VERSION 5.7 ;
  NOWIREEXTENSIONATPIN ON ;
  DIVIDERCHAR "/" ;
  BUSBITCHARS "[]" ;
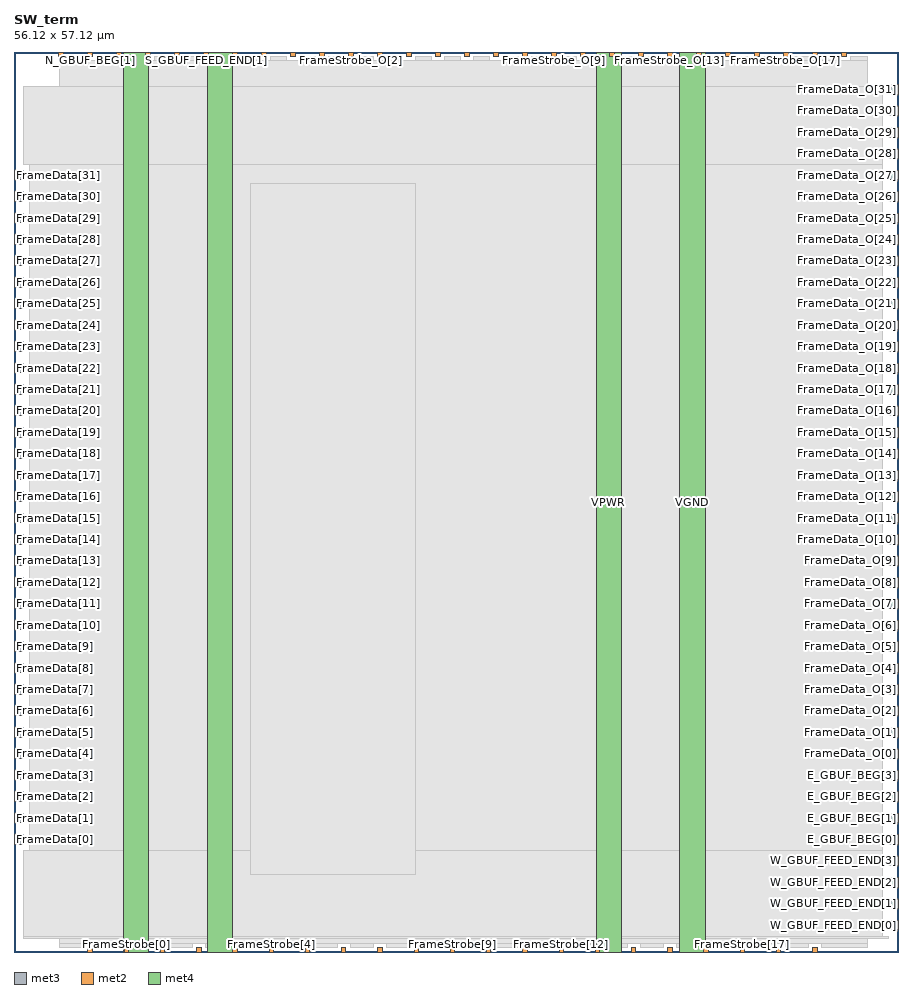
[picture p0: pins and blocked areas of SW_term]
MACRO SW_term
  CLASS BLOCK ;
  FOREIGN SW_term ;
  ORIGIN 0.000 0.000 ;
  SIZE 56.120 BY 57.120 ;
  PIN E_GBUF_BEG[0]
    DIRECTION OUTPUT ;
    USE SIGNAL ;
    ANTENNADIFFAREA 0.702900 ;
    PORT
      LAYER met3 ;
        RECT 55.520 6.840 56.120 7.440 ;
    END
  END E_GBUF_BEG[0]
  PIN E_GBUF_BEG[1]
    DIRECTION OUTPUT ;
    USE SIGNAL ;
    ANTENNADIFFAREA 0.702900 ;
    PORT
      LAYER met3 ;
        RECT 55.520 8.200 56.120 8.800 ;
    END
  END E_GBUF_BEG[1]
  PIN E_GBUF_BEG[2]
    DIRECTION OUTPUT ;
    USE SIGNAL ;
    ANTENNADIFFAREA 0.702900 ;
    PORT
      LAYER met3 ;
        RECT 55.520 9.560 56.120 10.160 ;
    END
  END E_GBUF_BEG[2]
  PIN E_GBUF_BEG[3]
    DIRECTION OUTPUT ;
    USE SIGNAL ;
    ANTENNADIFFAREA 0.702900 ;
    PORT
      LAYER met3 ;
        RECT 55.520 10.920 56.120 11.520 ;
    END
  END E_GBUF_BEG[3]
  PIN FrameData[0]
    DIRECTION INPUT ;
    USE SIGNAL ;
    ANTENNAGATEAREA 0.159000 ;
    PORT
      LAYER met3 ;
        RECT 0.000 6.840 0.600 7.440 ;
    END
  END FrameData[0]
  PIN FrameData[10]
    DIRECTION INPUT ;
    USE SIGNAL ;
    ANTENNAGATEAREA 0.159000 ;
    PORT
      LAYER met3 ;
        RECT 0.000 20.440 0.600 21.040 ;
    END
  END FrameData[10]
  PIN FrameData[11]
    DIRECTION INPUT ;
    USE SIGNAL ;
    ANTENNAGATEAREA 0.159000 ;
    PORT
      LAYER met3 ;
        RECT 0.000 21.800 0.600 22.400 ;
    END
  END FrameData[11]
  PIN FrameData[12]
    DIRECTION INPUT ;
    USE SIGNAL ;
    ANTENNAGATEAREA 0.318000 ;
    PORT
      LAYER met3 ;
        RECT 0.000 23.160 0.600 23.760 ;
    END
  END FrameData[12]
  PIN FrameData[13]
    DIRECTION INPUT ;
    USE SIGNAL ;
    ANTENNAGATEAREA 0.318000 ;
    PORT
      LAYER met3 ;
        RECT 0.000 24.520 0.600 25.120 ;
    END
  END FrameData[13]
  PIN FrameData[14]
    DIRECTION INPUT ;
    USE SIGNAL ;
    ANTENNAGATEAREA 0.318000 ;
    PORT
      LAYER met3 ;
        RECT 0.000 25.880 0.600 26.480 ;
    END
  END FrameData[14]
  PIN FrameData[15]
    DIRECTION INPUT ;
    USE SIGNAL ;
    ANTENNAGATEAREA 0.318000 ;
    PORT
      LAYER met3 ;
        RECT 0.000 27.240 0.600 27.840 ;
    END
  END FrameData[15]
  PIN FrameData[16]
    DIRECTION INPUT ;
    USE SIGNAL ;
    ANTENNAGATEAREA 0.318000 ;
    PORT
      LAYER met3 ;
        RECT 0.000 28.600 0.600 29.200 ;
    END
  END FrameData[16]
  PIN FrameData[17]
    DIRECTION INPUT ;
    USE SIGNAL ;
    ANTENNAGATEAREA 0.318000 ;
    PORT
      LAYER met3 ;
        RECT 0.000 29.960 0.600 30.560 ;
    END
  END FrameData[17]
  PIN FrameData[18]
    DIRECTION INPUT ;
    USE SIGNAL ;
    ANTENNAGATEAREA 0.318000 ;
    PORT
      LAYER met3 ;
        RECT 0.000 31.320 0.600 31.920 ;
    END
  END FrameData[18]
  PIN FrameData[19]
    DIRECTION INPUT ;
    USE SIGNAL ;
    ANTENNAGATEAREA 0.318000 ;
    PORT
      LAYER met3 ;
        RECT 0.000 32.680 0.600 33.280 ;
    END
  END FrameData[19]
  PIN FrameData[1]
    DIRECTION INPUT ;
    USE SIGNAL ;
    ANTENNAGATEAREA 0.159000 ;
    PORT
      LAYER met3 ;
        RECT 0.000 8.200 0.600 8.800 ;
    END
  END FrameData[1]
  PIN FrameData[20]
    DIRECTION INPUT ;
    USE SIGNAL ;
    ANTENNAGATEAREA 0.318000 ;
    PORT
      LAYER met3 ;
        RECT 0.000 34.040 0.600 34.640 ;
    END
  END FrameData[20]
  PIN FrameData[21]
    DIRECTION INPUT ;
    USE SIGNAL ;
    ANTENNAGATEAREA 0.318000 ;
    PORT
      LAYER met3 ;
        RECT 0.000 35.400 0.600 36.000 ;
    END
  END FrameData[21]
  PIN FrameData[22]
    DIRECTION INPUT ;
    USE SIGNAL ;
    ANTENNAGATEAREA 0.318000 ;
    PORT
      LAYER met3 ;
        RECT 0.000 36.760 0.600 37.360 ;
    END
  END FrameData[22]
  PIN FrameData[23]
    DIRECTION INPUT ;
    USE SIGNAL ;
    ANTENNAGATEAREA 0.318000 ;
    PORT
      LAYER met3 ;
        RECT 0.000 38.120 0.600 38.720 ;
    END
  END FrameData[23]
  PIN FrameData[24]
    DIRECTION INPUT ;
    USE SIGNAL ;
    ANTENNAGATEAREA 0.318000 ;
    PORT
      LAYER met3 ;
        RECT 0.000 39.480 0.600 40.080 ;
    END
  END FrameData[24]
  PIN FrameData[25]
    DIRECTION INPUT ;
    USE SIGNAL ;
    ANTENNAGATEAREA 0.318000 ;
    PORT
      LAYER met3 ;
        RECT 0.000 40.840 0.600 41.440 ;
    END
  END FrameData[25]
  PIN FrameData[26]
    DIRECTION INPUT ;
    USE SIGNAL ;
    ANTENNAGATEAREA 0.318000 ;
    PORT
      LAYER met3 ;
        RECT 0.000 42.200 0.600 42.800 ;
    END
  END FrameData[26]
  PIN FrameData[27]
    DIRECTION INPUT ;
    USE SIGNAL ;
    ANTENNAGATEAREA 0.318000 ;
    PORT
      LAYER met3 ;
        RECT 0.000 43.560 0.600 44.160 ;
    END
  END FrameData[27]
  PIN FrameData[28]
    DIRECTION INPUT ;
    USE SIGNAL ;
    ANTENNAGATEAREA 0.318000 ;
    PORT
      LAYER met3 ;
        RECT 0.000 44.920 0.600 45.520 ;
    END
  END FrameData[28]
  PIN FrameData[29]
    DIRECTION INPUT ;
    USE SIGNAL ;
    ANTENNAGATEAREA 0.318000 ;
    PORT
      LAYER met3 ;
        RECT 0.000 46.280 0.600 46.880 ;
    END
  END FrameData[29]
  PIN FrameData[2]
    DIRECTION INPUT ;
    USE SIGNAL ;
    ANTENNAGATEAREA 0.159000 ;
    PORT
      LAYER met3 ;
        RECT 0.000 9.560 0.600 10.160 ;
    END
  END FrameData[2]
  PIN FrameData[30]
    DIRECTION INPUT ;
    USE SIGNAL ;
    ANTENNAGATEAREA 0.318000 ;
    PORT
      LAYER met3 ;
        RECT 0.000 47.640 0.600 48.240 ;
    END
  END FrameData[30]
  PIN FrameData[31]
    DIRECTION INPUT ;
    USE SIGNAL ;
    ANTENNAGATEAREA 0.318000 ;
    PORT
      LAYER met3 ;
        RECT 0.000 49.000 0.600 49.600 ;
    END
  END FrameData[31]
  PIN FrameData[3]
    DIRECTION INPUT ;
    USE SIGNAL ;
    ANTENNAGATEAREA 0.159000 ;
    PORT
      LAYER met3 ;
        RECT 0.000 10.920 0.600 11.520 ;
    END
  END FrameData[3]
  PIN FrameData[4]
    DIRECTION INPUT ;
    USE SIGNAL ;
    ANTENNAGATEAREA 0.159000 ;
    PORT
      LAYER met3 ;
        RECT 0.000 12.280 0.600 12.880 ;
    END
  END FrameData[4]
  PIN FrameData[5]
    DIRECTION INPUT ;
    USE SIGNAL ;
    ANTENNAGATEAREA 0.159000 ;
    PORT
      LAYER met3 ;
        RECT 0.000 13.640 0.600 14.240 ;
    END
  END FrameData[5]
  PIN FrameData[6]
    DIRECTION INPUT ;
    USE SIGNAL ;
    ANTENNAGATEAREA 0.159000 ;
    PORT
      LAYER met3 ;
        RECT 0.000 15.000 0.600 15.600 ;
    END
  END FrameData[6]
  PIN FrameData[7]
    DIRECTION INPUT ;
    USE SIGNAL ;
    ANTENNAGATEAREA 0.159000 ;
    PORT
      LAYER met3 ;
        RECT 0.000 16.360 0.600 16.960 ;
    END
  END FrameData[7]
  PIN FrameData[8]
    DIRECTION INPUT ;
    USE SIGNAL ;
    ANTENNAGATEAREA 0.159000 ;
    PORT
      LAYER met3 ;
        RECT 0.000 17.720 0.600 18.320 ;
    END
  END FrameData[8]
  PIN FrameData[9]
    DIRECTION INPUT ;
    USE SIGNAL ;
    ANTENNAGATEAREA 0.159000 ;
    PORT
      LAYER met3 ;
        RECT 0.000 19.080 0.600 19.680 ;
    END
  END FrameData[9]
  PIN FrameData_O[0]
    DIRECTION OUTPUT ;
    USE SIGNAL ;
    ANTENNADIFFAREA 0.702900 ;
    PORT
      LAYER met3 ;
        RECT 55.520 12.280 56.120 12.880 ;
    END
  END FrameData_O[0]
  PIN FrameData_O[10]
    DIRECTION OUTPUT ;
    USE SIGNAL ;
    ANTENNADIFFAREA 0.702900 ;
    PORT
      LAYER met3 ;
        RECT 55.520 25.880 56.120 26.480 ;
    END
  END FrameData_O[10]
  PIN FrameData_O[11]
    DIRECTION OUTPUT ;
    USE SIGNAL ;
    ANTENNADIFFAREA 0.702900 ;
    PORT
      LAYER met3 ;
        RECT 55.520 27.240 56.120 27.840 ;
    END
  END FrameData_O[11]
  PIN FrameData_O[12]
    DIRECTION OUTPUT ;
    USE SIGNAL ;
    ANTENNADIFFAREA 0.702900 ;
    PORT
      LAYER met3 ;
        RECT 55.520 28.600 56.120 29.200 ;
    END
  END FrameData_O[12]
  PIN FrameData_O[13]
    DIRECTION OUTPUT ;
    USE SIGNAL ;
    ANTENNADIFFAREA 0.702900 ;
    PORT
      LAYER met3 ;
        RECT 55.520 29.960 56.120 30.560 ;
    END
  END FrameData_O[13]
  PIN FrameData_O[14]
    DIRECTION OUTPUT ;
    USE SIGNAL ;
    ANTENNADIFFAREA 0.702900 ;
    PORT
      LAYER met3 ;
        RECT 55.520 31.320 56.120 31.920 ;
    END
  END FrameData_O[14]
  PIN FrameData_O[15]
    DIRECTION OUTPUT ;
    USE SIGNAL ;
    ANTENNADIFFAREA 0.702900 ;
    PORT
      LAYER met3 ;
        RECT 55.520 32.680 56.120 33.280 ;
    END
  END FrameData_O[15]
  PIN FrameData_O[16]
    DIRECTION OUTPUT ;
    USE SIGNAL ;
    ANTENNADIFFAREA 0.702900 ;
    PORT
      LAYER met3 ;
        RECT 55.520 34.040 56.120 34.640 ;
    END
  END FrameData_O[16]
  PIN FrameData_O[17]
    DIRECTION OUTPUT ;
    USE SIGNAL ;
    ANTENNADIFFAREA 0.702900 ;
    PORT
      LAYER met3 ;
        RECT 55.520 35.400 56.120 36.000 ;
    END
  END FrameData_O[17]
  PIN FrameData_O[18]
    DIRECTION OUTPUT ;
    USE SIGNAL ;
    ANTENNADIFFAREA 0.702900 ;
    PORT
      LAYER met3 ;
        RECT 55.520 36.760 56.120 37.360 ;
    END
  END FrameData_O[18]
  PIN FrameData_O[19]
    DIRECTION OUTPUT ;
    USE SIGNAL ;
    ANTENNADIFFAREA 0.702900 ;
    PORT
      LAYER met3 ;
        RECT 55.520 38.120 56.120 38.720 ;
    END
  END FrameData_O[19]
  PIN FrameData_O[1]
    DIRECTION OUTPUT ;
    USE SIGNAL ;
    ANTENNADIFFAREA 0.702900 ;
    PORT
      LAYER met3 ;
        RECT 55.520 13.640 56.120 14.240 ;
    END
  END FrameData_O[1]
  PIN FrameData_O[20]
    DIRECTION OUTPUT ;
    USE SIGNAL ;
    ANTENNADIFFAREA 0.702900 ;
    PORT
      LAYER met3 ;
        RECT 55.520 39.480 56.120 40.080 ;
    END
  END FrameData_O[20]
  PIN FrameData_O[21]
    DIRECTION OUTPUT ;
    USE SIGNAL ;
    ANTENNADIFFAREA 0.702900 ;
    PORT
      LAYER met3 ;
        RECT 55.520 40.840 56.120 41.440 ;
    END
  END FrameData_O[21]
  PIN FrameData_O[22]
    DIRECTION OUTPUT ;
    USE SIGNAL ;
    ANTENNADIFFAREA 0.702900 ;
    PORT
      LAYER met3 ;
        RECT 55.520 42.200 56.120 42.800 ;
    END
  END FrameData_O[22]
  PIN FrameData_O[23]
    DIRECTION OUTPUT ;
    USE SIGNAL ;
    ANTENNADIFFAREA 0.702900 ;
    PORT
      LAYER met3 ;
        RECT 55.520 43.560 56.120 44.160 ;
    END
  END FrameData_O[23]
  PIN FrameData_O[24]
    DIRECTION OUTPUT ;
    USE SIGNAL ;
    ANTENNADIFFAREA 0.702900 ;
    PORT
      LAYER met3 ;
        RECT 55.520 44.920 56.120 45.520 ;
    END
  END FrameData_O[24]
  PIN FrameData_O[25]
    DIRECTION OUTPUT ;
    USE SIGNAL ;
    ANTENNADIFFAREA 0.702900 ;
    PORT
      LAYER met3 ;
        RECT 55.520 46.280 56.120 46.880 ;
    END
  END FrameData_O[25]
  PIN FrameData_O[26]
    DIRECTION OUTPUT ;
    USE SIGNAL ;
    ANTENNADIFFAREA 0.702900 ;
    PORT
      LAYER met3 ;
        RECT 55.520 47.640 56.120 48.240 ;
    END
  END FrameData_O[26]
  PIN FrameData_O[27]
    DIRECTION OUTPUT ;
    USE SIGNAL ;
    ANTENNADIFFAREA 0.702900 ;
    PORT
      LAYER met3 ;
        RECT 55.520 49.000 56.120 49.600 ;
    END
  END FrameData_O[27]
  PIN FrameData_O[28]
    DIRECTION OUTPUT ;
    USE SIGNAL ;
    ANTENNADIFFAREA 0.702900 ;
    PORT
      LAYER met3 ;
        RECT 55.520 50.360 56.120 50.960 ;
    END
  END FrameData_O[28]
  PIN FrameData_O[29]
    DIRECTION OUTPUT ;
    USE SIGNAL ;
    ANTENNADIFFAREA 0.702900 ;
    PORT
      LAYER met3 ;
        RECT 55.520 51.720 56.120 52.320 ;
    END
  END FrameData_O[29]
  PIN FrameData_O[2]
    DIRECTION OUTPUT ;
    USE SIGNAL ;
    ANTENNADIFFAREA 0.702900 ;
    PORT
      LAYER met3 ;
        RECT 55.520 15.000 56.120 15.600 ;
    END
  END FrameData_O[2]
  PIN FrameData_O[30]
    DIRECTION OUTPUT ;
    USE SIGNAL ;
    ANTENNADIFFAREA 0.702900 ;
    PORT
      LAYER met3 ;
        RECT 55.520 53.080 56.120 53.680 ;
    END
  END FrameData_O[30]
  PIN FrameData_O[31]
    DIRECTION OUTPUT ;
    USE SIGNAL ;
    ANTENNADIFFAREA 0.702900 ;
    PORT
      LAYER met3 ;
        RECT 55.520 54.440 56.120 55.040 ;
    END
  END FrameData_O[31]
  PIN FrameData_O[3]
    DIRECTION OUTPUT ;
    USE SIGNAL ;
    ANTENNADIFFAREA 0.702900 ;
    PORT
      LAYER met3 ;
        RECT 55.520 16.360 56.120 16.960 ;
    END
  END FrameData_O[3]
  PIN FrameData_O[4]
    DIRECTION OUTPUT ;
    USE SIGNAL ;
    ANTENNADIFFAREA 0.702900 ;
    PORT
      LAYER met3 ;
        RECT 55.520 17.720 56.120 18.320 ;
    END
  END FrameData_O[4]
  PIN FrameData_O[5]
    DIRECTION OUTPUT ;
    USE SIGNAL ;
    ANTENNADIFFAREA 0.702900 ;
    PORT
      LAYER met3 ;
        RECT 55.520 19.080 56.120 19.680 ;
    END
  END FrameData_O[5]
  PIN FrameData_O[6]
    DIRECTION OUTPUT ;
    USE SIGNAL ;
    ANTENNADIFFAREA 0.702900 ;
    PORT
      LAYER met3 ;
        RECT 55.520 20.440 56.120 21.040 ;
    END
  END FrameData_O[6]
  PIN FrameData_O[7]
    DIRECTION OUTPUT ;
    USE SIGNAL ;
    ANTENNADIFFAREA 0.702900 ;
    PORT
      LAYER met3 ;
        RECT 55.520 21.800 56.120 22.400 ;
    END
  END FrameData_O[7]
  PIN FrameData_O[8]
    DIRECTION OUTPUT ;
    USE SIGNAL ;
    ANTENNADIFFAREA 0.702900 ;
    PORT
      LAYER met3 ;
        RECT 55.520 23.160 56.120 23.760 ;
    END
  END FrameData_O[8]
  PIN FrameData_O[9]
    DIRECTION OUTPUT ;
    USE SIGNAL ;
    ANTENNADIFFAREA 0.702900 ;
    PORT
      LAYER met3 ;
        RECT 55.520 24.520 56.120 25.120 ;
    END
  END FrameData_O[9]
  PIN FrameStrobe[0]
    DIRECTION INPUT ;
    USE SIGNAL ;
    ANTENNAGATEAREA 3.339000 ;
    PORT
      LAYER met2 ;
        RECT 6.990 0.000 7.270 0.280 ;
    END
  END FrameStrobe[0]
  PIN FrameStrobe[10]
    DIRECTION INPUT ;
    USE SIGNAL ;
    ANTENNAGATEAREA 0.159000 ;
    PORT
      LAYER met2 ;
        RECT 29.990 0.000 30.270 0.280 ;
    END
  END FrameStrobe[10]
  PIN FrameStrobe[11]
    DIRECTION INPUT ;
    USE SIGNAL ;
    ANTENNAGATEAREA 0.159000 ;
    PORT
      LAYER met2 ;
        RECT 32.290 0.000 32.570 0.280 ;
    END
  END FrameStrobe[11]
  PIN FrameStrobe[12]
    DIRECTION INPUT ;
    USE SIGNAL ;
    ANTENNAGATEAREA 0.159000 ;
    PORT
      LAYER met2 ;
        RECT 34.590 0.000 34.870 0.280 ;
    END
  END FrameStrobe[12]
  PIN FrameStrobe[13]
    DIRECTION INPUT ;
    USE SIGNAL ;
    ANTENNAGATEAREA 0.159000 ;
    PORT
      LAYER met2 ;
        RECT 36.890 0.000 37.170 0.280 ;
    END
  END FrameStrobe[13]
  PIN FrameStrobe[14]
    DIRECTION INPUT ;
    USE SIGNAL ;
    ANTENNAGATEAREA 0.159000 ;
    PORT
      LAYER met2 ;
        RECT 39.190 0.000 39.470 0.280 ;
    END
  END FrameStrobe[14]
  PIN FrameStrobe[15]
    DIRECTION INPUT ;
    USE SIGNAL ;
    ANTENNAGATEAREA 0.159000 ;
    PORT
      LAYER met2 ;
        RECT 41.490 0.000 41.770 0.280 ;
    END
  END FrameStrobe[15]
  PIN FrameStrobe[16]
    DIRECTION INPUT ;
    USE SIGNAL ;
    ANTENNAGATEAREA 0.159000 ;
    PORT
      LAYER met2 ;
        RECT 43.790 0.000 44.070 0.280 ;
    END
  END FrameStrobe[16]
  PIN FrameStrobe[17]
    DIRECTION INPUT ;
    USE SIGNAL ;
    ANTENNAGATEAREA 0.159000 ;
    PORT
      LAYER met2 ;
        RECT 46.090 0.000 46.370 0.280 ;
    END
  END FrameStrobe[17]
  PIN FrameStrobe[18]
    DIRECTION INPUT ;
    USE SIGNAL ;
    ANTENNAGATEAREA 0.159000 ;
    PORT
      LAYER met2 ;
        RECT 48.390 0.000 48.670 0.280 ;
    END
  END FrameStrobe[18]
  PIN FrameStrobe[19]
    DIRECTION INPUT ;
    USE SIGNAL ;
    ANTENNAGATEAREA 0.159000 ;
    PORT
      LAYER met2 ;
        RECT 50.690 0.000 50.970 0.280 ;
    END
  END FrameStrobe[19]
  PIN FrameStrobe[1]
    DIRECTION INPUT ;
    USE SIGNAL ;
    ANTENNAGATEAREA 0.159000 ;
    PORT
      LAYER met2 ;
        RECT 9.290 0.000 9.570 0.280 ;
    END
  END FrameStrobe[1]
  PIN FrameStrobe[2]
    DIRECTION INPUT ;
    USE SIGNAL ;
    ANTENNAGATEAREA 0.159000 ;
    PORT
      LAYER met2 ;
        RECT 11.590 0.000 11.870 0.280 ;
    END
  END FrameStrobe[2]
  PIN FrameStrobe[3]
    DIRECTION INPUT ;
    USE SIGNAL ;
    ANTENNAGATEAREA 0.159000 ;
    PORT
      LAYER met2 ;
        RECT 13.890 0.000 14.170 0.280 ;
    END
  END FrameStrobe[3]
  PIN FrameStrobe[4]
    DIRECTION INPUT ;
    USE SIGNAL ;
    ANTENNAGATEAREA 0.159000 ;
    PORT
      LAYER met2 ;
        RECT 16.190 0.000 16.470 0.280 ;
    END
  END FrameStrobe[4]
  PIN FrameStrobe[5]
    DIRECTION INPUT ;
    USE SIGNAL ;
    ANTENNAGATEAREA 0.159000 ;
    PORT
      LAYER met2 ;
        RECT 18.490 0.000 18.770 0.280 ;
    END
  END FrameStrobe[5]
  PIN FrameStrobe[6]
    DIRECTION INPUT ;
    USE SIGNAL ;
    ANTENNAGATEAREA 0.159000 ;
    PORT
      LAYER met2 ;
        RECT 20.790 0.000 21.070 0.280 ;
    END
  END FrameStrobe[6]
  PIN FrameStrobe[7]
    DIRECTION INPUT ;
    USE SIGNAL ;
    ANTENNAGATEAREA 0.159000 ;
    PORT
      LAYER met2 ;
        RECT 23.090 0.000 23.370 0.280 ;
    END
  END FrameStrobe[7]
  PIN FrameStrobe[8]
    DIRECTION INPUT ;
    USE SIGNAL ;
    ANTENNAGATEAREA 0.159000 ;
    PORT
      LAYER met2 ;
        RECT 25.390 0.000 25.670 0.280 ;
    END
  END FrameStrobe[8]
  PIN FrameStrobe[9]
    DIRECTION INPUT ;
    USE SIGNAL ;
    ANTENNAGATEAREA 0.159000 ;
    PORT
      LAYER met2 ;
        RECT 27.690 0.000 27.970 0.280 ;
    END
  END FrameStrobe[9]
  PIN FrameStrobe_O[0]
    DIRECTION OUTPUT ;
    USE SIGNAL ;
    ANTENNADIFFAREA 0.702900 ;
    PORT
      LAYER met2 ;
        RECT 17.570 56.840 17.850 57.120 ;
    END
  END FrameStrobe_O[0]
  PIN FrameStrobe_O[10]
    DIRECTION OUTPUT ;
    USE SIGNAL ;
    ANTENNADIFFAREA 0.702900 ;
    PORT
      LAYER met2 ;
        RECT 35.970 56.840 36.250 57.120 ;
    END
  END FrameStrobe_O[10]
  PIN FrameStrobe_O[11]
    DIRECTION OUTPUT ;
    USE SIGNAL ;
    ANTENNADIFFAREA 0.702900 ;
    PORT
      LAYER met2 ;
        RECT 37.810 56.840 38.090 57.120 ;
    END
  END FrameStrobe_O[11]
  PIN FrameStrobe_O[12]
    DIRECTION OUTPUT ;
    USE SIGNAL ;
    ANTENNADIFFAREA 0.702900 ;
    PORT
      LAYER met2 ;
        RECT 39.650 56.840 39.930 57.120 ;
    END
  END FrameStrobe_O[12]
  PIN FrameStrobe_O[13]
    DIRECTION OUTPUT ;
    USE SIGNAL ;
    ANTENNADIFFAREA 0.702900 ;
    PORT
      LAYER met2 ;
        RECT 41.490 56.840 41.770 57.120 ;
    END
  END FrameStrobe_O[13]
  PIN FrameStrobe_O[14]
    DIRECTION OUTPUT ;
    USE SIGNAL ;
    ANTENNADIFFAREA 0.702900 ;
    PORT
      LAYER met2 ;
        RECT 43.330 56.840 43.610 57.120 ;
    END
  END FrameStrobe_O[14]
  PIN FrameStrobe_O[15]
    DIRECTION OUTPUT ;
    USE SIGNAL ;
    ANTENNADIFFAREA 0.702900 ;
    PORT
      LAYER met2 ;
        RECT 45.170 56.840 45.450 57.120 ;
    END
  END FrameStrobe_O[15]
  PIN FrameStrobe_O[16]
    DIRECTION OUTPUT ;
    USE SIGNAL ;
    ANTENNADIFFAREA 0.702900 ;
    PORT
      LAYER met2 ;
        RECT 47.010 56.840 47.290 57.120 ;
    END
  END FrameStrobe_O[16]
  PIN FrameStrobe_O[17]
    DIRECTION OUTPUT ;
    USE SIGNAL ;
    ANTENNADIFFAREA 0.702900 ;
    PORT
      LAYER met2 ;
        RECT 48.850 56.840 49.130 57.120 ;
    END
  END FrameStrobe_O[17]
  PIN FrameStrobe_O[18]
    DIRECTION OUTPUT ;
    USE SIGNAL ;
    ANTENNADIFFAREA 0.702900 ;
    PORT
      LAYER met2 ;
        RECT 50.690 56.840 50.970 57.120 ;
    END
  END FrameStrobe_O[18]
  PIN FrameStrobe_O[19]
    DIRECTION OUTPUT ;
    USE SIGNAL ;
    ANTENNADIFFAREA 0.702900 ;
    PORT
      LAYER met2 ;
        RECT 52.530 56.840 52.810 57.120 ;
    END
  END FrameStrobe_O[19]
  PIN FrameStrobe_O[1]
    DIRECTION OUTPUT ;
    USE SIGNAL ;
    ANTENNADIFFAREA 0.702900 ;
    PORT
      LAYER met2 ;
        RECT 19.410 56.840 19.690 57.120 ;
    END
  END FrameStrobe_O[1]
  PIN FrameStrobe_O[2]
    DIRECTION OUTPUT ;
    USE SIGNAL ;
    ANTENNADIFFAREA 0.702900 ;
    PORT
      LAYER met2 ;
        RECT 21.250 56.840 21.530 57.120 ;
    END
  END FrameStrobe_O[2]
  PIN FrameStrobe_O[3]
    DIRECTION OUTPUT ;
    USE SIGNAL ;
    ANTENNADIFFAREA 0.702900 ;
    PORT
      LAYER met2 ;
        RECT 23.090 56.840 23.370 57.120 ;
    END
  END FrameStrobe_O[3]
  PIN FrameStrobe_O[4]
    DIRECTION OUTPUT ;
    USE SIGNAL ;
    ANTENNADIFFAREA 0.702900 ;
    PORT
      LAYER met2 ;
        RECT 24.930 56.840 25.210 57.120 ;
    END
  END FrameStrobe_O[4]
  PIN FrameStrobe_O[5]
    DIRECTION OUTPUT ;
    USE SIGNAL ;
    ANTENNADIFFAREA 0.702900 ;
    PORT
      LAYER met2 ;
        RECT 26.770 56.840 27.050 57.120 ;
    END
  END FrameStrobe_O[5]
  PIN FrameStrobe_O[6]
    DIRECTION OUTPUT ;
    USE SIGNAL ;
    ANTENNADIFFAREA 0.702900 ;
    PORT
      LAYER met2 ;
        RECT 28.610 56.840 28.890 57.120 ;
    END
  END FrameStrobe_O[6]
  PIN FrameStrobe_O[7]
    DIRECTION OUTPUT ;
    USE SIGNAL ;
    ANTENNADIFFAREA 0.702900 ;
    PORT
      LAYER met2 ;
        RECT 30.450 56.840 30.730 57.120 ;
    END
  END FrameStrobe_O[7]
  PIN FrameStrobe_O[8]
    DIRECTION OUTPUT ;
    USE SIGNAL ;
    ANTENNADIFFAREA 0.702900 ;
    PORT
      LAYER met2 ;
        RECT 32.290 56.840 32.570 57.120 ;
    END
  END FrameStrobe_O[8]
  PIN FrameStrobe_O[9]
    DIRECTION OUTPUT ;
    USE SIGNAL ;
    ANTENNADIFFAREA 0.702900 ;
    PORT
      LAYER met2 ;
        RECT 34.130 56.840 34.410 57.120 ;
    END
  END FrameStrobe_O[9]
  PIN N_GBUF_BEG[0]
    DIRECTION OUTPUT ;
    USE SIGNAL ;
    ANTENNADIFFAREA 0.702900 ;
    PORT
      LAYER met2 ;
        RECT 2.850 56.840 3.130 57.120 ;
    END
  END N_GBUF_BEG[0]
  PIN N_GBUF_BEG[1]
    DIRECTION OUTPUT ;
    USE SIGNAL ;
    ANTENNADIFFAREA 0.702900 ;
    PORT
      LAYER met2 ;
        RECT 4.690 56.840 4.970 57.120 ;
    END
  END N_GBUF_BEG[1]
  PIN N_GBUF_BEG[2]
    DIRECTION OUTPUT ;
    USE SIGNAL ;
    ANTENNADIFFAREA 0.702900 ;
    PORT
      LAYER met2 ;
        RECT 6.530 56.840 6.810 57.120 ;
    END
  END N_GBUF_BEG[2]
  PIN N_GBUF_BEG[3]
    DIRECTION OUTPUT ;
    USE SIGNAL ;
    ANTENNADIFFAREA 0.702900 ;
    PORT
      LAYER met2 ;
        RECT 8.370 56.840 8.650 57.120 ;
    END
  END N_GBUF_BEG[3]
  PIN SYS_RESET_RESET_top
    DIRECTION INPUT ;
    USE SIGNAL ;
    ANTENNAGATEAREA 0.621000 ;
    PORT
      LAYER met2 ;
        RECT 4.690 0.000 4.970 0.280 ;
    END
  END SYS_RESET_RESET_top
  PIN S_GBUF_FEED_END[0]
    DIRECTION INPUT ;
    USE SIGNAL ;
    ANTENNAGATEAREA 0.636000 ;
    PORT
      LAYER met2 ;
        RECT 10.210 56.840 10.490 57.120 ;
    END
  END S_GBUF_FEED_END[0]
  PIN S_GBUF_FEED_END[1]
    DIRECTION INPUT ;
    USE SIGNAL ;
    ANTENNAGATEAREA 0.636000 ;
    PORT
      LAYER met2 ;
        RECT 12.050 56.840 12.330 57.120 ;
    END
  END S_GBUF_FEED_END[1]
  PIN S_GBUF_FEED_END[2]
    DIRECTION INPUT ;
    USE SIGNAL ;
    ANTENNAGATEAREA 0.636000 ;
    PORT
      LAYER met2 ;
        RECT 13.890 56.840 14.170 57.120 ;
    END
  END S_GBUF_FEED_END[2]
  PIN S_GBUF_FEED_END[3]
    DIRECTION INPUT ;
    USE SIGNAL ;
    ANTENNAGATEAREA 0.636000 ;
    PORT
      LAYER met2 ;
        RECT 15.730 56.840 16.010 57.120 ;
    END
  END S_GBUF_FEED_END[3]
  PIN VGND
    DIRECTION INOUT ;
    USE GROUND ;
    PORT
      LAYER met4 ;
        RECT 12.260 0.000 13.860 57.120 ;
    END
    PORT
      LAYER met4 ;
        RECT 42.260 0.000 43.860 57.120 ;
    END
  END VGND
  PIN VPWR
    DIRECTION INOUT ;
    USE POWER ;
    PORT
      LAYER met4 ;
        RECT 6.960 0.000 8.560 57.120 ;
    END
    PORT
      LAYER met4 ;
        RECT 36.960 0.000 38.560 57.120 ;
    END
  END VPWR
  PIN W_GBUF_FEED_END[0]
    DIRECTION INPUT ;
    USE SIGNAL ;
    ANTENNAGATEAREA 0.636000 ;
    PORT
      LAYER met3 ;
        RECT 55.520 1.400 56.120 2.000 ;
    END
  END W_GBUF_FEED_END[0]
  PIN W_GBUF_FEED_END[1]
    DIRECTION INPUT ;
    USE SIGNAL ;
    ANTENNAGATEAREA 0.636000 ;
    PORT
      LAYER met3 ;
        RECT 55.520 2.760 56.120 3.360 ;
    END
  END W_GBUF_FEED_END[1]
  PIN W_GBUF_FEED_END[2]
    DIRECTION INPUT ;
    USE SIGNAL ;
    ANTENNAGATEAREA 0.636000 ;
    PORT
      LAYER met3 ;
        RECT 55.520 4.120 56.120 4.720 ;
    END
  END W_GBUF_FEED_END[2]
  PIN W_GBUF_FEED_END[3]
    DIRECTION INPUT ;
    USE SIGNAL ;
    ANTENNAGATEAREA 0.636000 ;
    PORT
      LAYER met3 ;
        RECT 55.520 5.480 56.120 6.080 ;
    END
  END W_GBUF_FEED_END[3]
  OBS
      LAYER nwell ;
        RECT 2.570 2.635 53.550 54.590 ;
      LAYER li1 ;
        RECT 2.760 2.635 53.360 54.485 ;
      LAYER met1 ;
        RECT 2.760 2.480 54.210 54.640 ;
      LAYER met2 ;
        RECT 3.410 56.560 4.410 56.850 ;
        RECT 5.250 56.560 6.250 56.850 ;
        RECT 7.090 56.560 8.090 56.850 ;
        RECT 8.930 56.560 9.930 56.850 ;
        RECT 10.770 56.560 11.770 56.850 ;
        RECT 12.610 56.560 13.610 56.850 ;
        RECT 14.450 56.560 15.450 56.850 ;
        RECT 16.290 56.560 17.290 56.850 ;
        RECT 18.130 56.560 19.130 56.850 ;
        RECT 19.970 56.560 20.970 56.850 ;
        RECT 21.810 56.560 22.810 56.850 ;
        RECT 23.650 56.560 24.650 56.850 ;
        RECT 25.490 56.560 26.490 56.850 ;
        RECT 27.330 56.560 28.330 56.850 ;
        RECT 29.170 56.560 30.170 56.850 ;
        RECT 31.010 56.560 32.010 56.850 ;
        RECT 32.850 56.560 33.850 56.850 ;
        RECT 34.690 56.560 35.690 56.850 ;
        RECT 36.530 56.560 37.530 56.850 ;
        RECT 38.370 56.560 39.370 56.850 ;
        RECT 40.210 56.560 41.210 56.850 ;
        RECT 42.050 56.560 43.050 56.850 ;
        RECT 43.890 56.560 44.890 56.850 ;
        RECT 45.730 56.560 46.730 56.850 ;
        RECT 47.570 56.560 48.570 56.850 ;
        RECT 49.410 56.560 50.410 56.850 ;
        RECT 51.250 56.560 52.250 56.850 ;
        RECT 53.090 56.560 54.190 56.850 ;
        RECT 2.860 0.560 54.190 56.560 ;
        RECT 2.860 0.270 4.410 0.560 ;
        RECT 5.250 0.270 6.710 0.560 ;
        RECT 7.550 0.270 9.010 0.560 ;
        RECT 9.850 0.270 11.310 0.560 ;
        RECT 12.150 0.270 13.610 0.560 ;
        RECT 14.450 0.270 15.910 0.560 ;
        RECT 16.750 0.270 18.210 0.560 ;
        RECT 19.050 0.270 20.510 0.560 ;
        RECT 21.350 0.270 22.810 0.560 ;
        RECT 23.650 0.270 25.110 0.560 ;
        RECT 25.950 0.270 27.410 0.560 ;
        RECT 28.250 0.270 29.710 0.560 ;
        RECT 30.550 0.270 32.010 0.560 ;
        RECT 32.850 0.270 34.310 0.560 ;
        RECT 35.150 0.270 36.610 0.560 ;
        RECT 37.450 0.270 38.910 0.560 ;
        RECT 39.750 0.270 41.210 0.560 ;
        RECT 42.050 0.270 43.510 0.560 ;
        RECT 44.350 0.270 45.810 0.560 ;
        RECT 46.650 0.270 48.110 0.560 ;
        RECT 48.950 0.270 50.410 0.560 ;
        RECT 51.250 0.270 54.190 0.560 ;
      LAYER met3 ;
        RECT 0.600 50.000 55.120 54.905 ;
        RECT 1.000 6.440 55.120 50.000 ;
        RECT 0.600 1.000 55.120 6.440 ;
        RECT 0.600 0.855 55.520 1.000 ;
      LAYER met4 ;
        RECT 15.015 4.935 25.465 48.785 ;
  END
END SW_term
END LIBRARY

